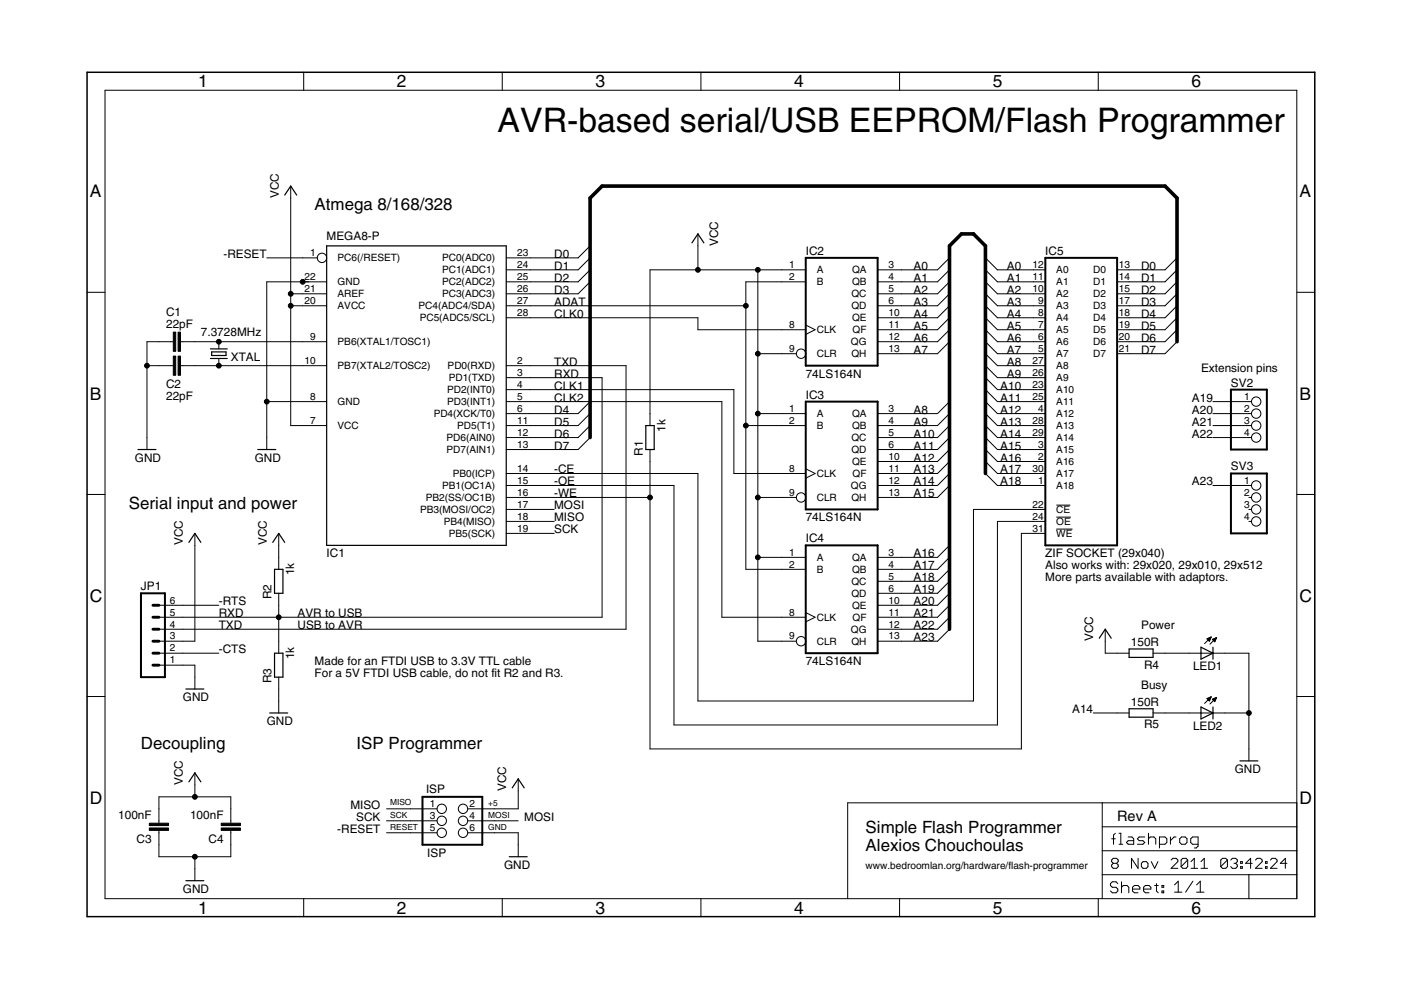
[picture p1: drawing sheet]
<svg xmlns="http://www.w3.org/2000/svg" width="297mm" height="210mm" viewBox="0 0 297 210" stroke-linecap="round" stroke-linejoin="round" font-family="sans-serif">
<defs><g id="words">
<text font-size="7.2" x="105.5" y="28">AVR-based serial/USB EEPROM/Flash Programmer</text>
<g font-size="3.7">
<text x="42" y="18.5">1</text>
<text x="84.1" y="18.5">2</text>
<text x="126.2" y="18.5">3</text>
<text x="168.4" y="18.5">4</text>
<text x="210.5" y="18.5">5</text>
<text x="252.6" y="18.5">6</text>
<text x="19.1" y="41.9">A</text>
<text x="275.6" y="41.9">A</text>
<text x="19.1" y="84.7">B</text>
<text x="275.6" y="84.7">B</text>
<text x="19.1" y="127.6">C</text>
<text x="275.6" y="127.6">C</text>
<text x="19.1" y="170.4">D</text>
<text x="275.6" y="170.4">D</text>
<text x="42" y="193.7">1</text>
<text x="84.1" y="193.7">2</text>
<text x="126.2" y="193.7">3</text>
<text x="168.4" y="193.7">4</text>
<text x="210.5" y="193.7">5</text>
<text x="252.6" y="193.7">6</text>
</g>
<g font-size="3.6">
<text x="66.7" y="44.5">Atmega 8/168/328</text>
<text x="27.3" y="108">Serial input and power</text>
<text x="29.9" y="158.8">Decoupling</text>
<text x="75.6" y="158.8">ISP Programmer</text>
<text x="183.5" y="176.6">Simple Flash Programmer</text>
<text x="183.5" y="180.4">Alexios Chouchoulas</text>
</g>
<text font-size="3.1" x="236.9" y="174">Rev A</text>
<g font-size="2.5">
<text x="59.1" y="42" transform="rotate(-90 59.1 42)">VCC</text>
<text x="69.2" y="50.9">MEGA8-P</text>
<text x="152.3" y="52.1" transform="rotate(-90 152.3 52.1)">VCC</text>
<text x="47.4" y="54.7">-RESET</text>
<text x="117.5" y="54.7">D0</text>
<text x="117.5" y="57.2">D1</text>
<text x="117.5" y="59.8">D2</text>
<text x="170.8" y="54">IC2</text>
<text x="193.7" y="57.2">A0</text>
<text x="193.7" y="59.8">A1</text>
<text x="213.5" y="57.2">A0</text>
<text x="213.5" y="59.8">A1</text>
<text x="221.6" y="54">IC5</text>
<text x="241.9" y="57.2">D0</text>
<text x="241.9" y="59.8">D1</text>
<text x="117.5" y="62.3">D3</text>
<text x="117.5" y="64.8">ADAT</text>
<text x="193.7" y="62.3">A2</text>
<text x="193.7" y="64.8">A3</text>
<text x="213.5" y="62.3">A2</text>
<text x="213.5" y="64.8">A3</text>
<text x="241.9" y="62.3">D2</text>
<text x="241.9" y="64.8">D3</text>
<text x="35.2" y="69.5">22pF</text>
<text x="35.2" y="67">C1</text>
<text x="42.6" y="71.2">7.3728MHz</text>
<text x="117.5" y="67.4">CLK0</text>
<text x="193.7" y="67.4">A4</text>
<text x="193.7" y="69.9">A5</text>
<text x="213.5" y="67.4">A4</text>
<text x="213.5" y="69.9">A5</text>
<text x="241.9" y="67.4">D4</text>
<text x="241.9" y="69.9">D5</text>
<text x="48.9" y="76.5">XTAL</text>
<text x="117.5" y="77.5">TXD</text>
<text x="193.7" y="72.5">A6</text>
<text x="193.7" y="75">A7</text>
<text x="213.5" y="72.5">A6</text>
<text x="213.5" y="75">A7</text>
<text x="213.5" y="77.5">A8</text>
<text x="241.9" y="72.5">D6</text>
<text x="241.9" y="75">D7</text>
<text x="35.2" y="82.2">C2</text>
<text x="117.5" y="80.1">RXD</text>
<text x="117.5" y="82.6">CLK1</text>
<text x="170.8" y="80.1">74LS164N</text>
<text x="212.1" y="82.6">A10</text>
<text x="213.5" y="80.1">A9</text>
<text x="254.6" y="78.8">Extension pins</text>
<text x="261" y="82">SV2</text>
<text x="35.2" y="84.8">22pF</text>
<text x="117.5" y="87.7">D4</text>
<text x="117.5" y="85.2">CLK2</text>
<text x="170.8" y="84.5">IC3</text>
<text x="193.7" y="87.7">A8</text>
<text x="212.1" y="85.2">A11</text>
<text x="212.1" y="87.7">A12</text>
<text x="252.7" y="85.2">A19</text>
<text x="252.7" y="87.7">A20</text>
<text x="117.5" y="90.2">D5</text>
<text x="117.5" y="92.8">D6</text>
<text x="117.5" y="95.3">D7</text>
<text x="141.1" y="91.5" transform="rotate(-90 141.1 91.5)">1k</text>
<text x="193.7" y="90.2">A9</text>
<text x="193.7" y="92.8">A10</text>
<text x="193.7" y="95.3">A11</text>
<text x="212.1" y="90.2">A13</text>
<text x="212.1" y="92.8">A14</text>
<text x="212.1" y="95.3">A15</text>
<text x="252.7" y="90.2">A21</text>
<text x="252.7" y="92.8">A22</text>
<text x="28.6" y="97.9">GND</text>
<text x="54" y="97.9">GND</text>
<text x="117.5" y="100.4">-CE</text>
<text x="136.3" y="96.6" transform="rotate(-90 136.3 96.6)">R1</text>
<text x="193.7" y="97.9">A12</text>
<text x="193.7" y="100.4">A13</text>
<text x="212.1" y="97.9">A16</text>
<text x="212.1" y="100.4">A17</text>
<text x="261" y="99.8">SV3</text>
<text x="117.5" y="105.5">-WE</text>
<text x="117.5" y="102.9">-OE</text>
<text x="193.7" y="102.9">A14</text>
<text x="193.7" y="105.5">A15</text>
<text x="212.1" y="102.9">A18</text>
<text x="252.7" y="102.9">A23</text>
<text x="117.5" y="110.5">MISO</text>
<text x="117.5" y="113.1">SCK</text>
<text x="117.5" y="108">MOSI</text>
<text x="170.8" y="110.5">74LS164N</text>
<text x="38.8" y="115.6" transform="rotate(-90 38.8 115.6)">VCC</text>
<text x="56.6" y="115.6" transform="rotate(-90 56.6 115.6)">VCC</text>
<text x="69.2" y="118.2">IC1</text>
<text x="170.8" y="115">IC4</text>
<text x="193.7" y="118.2">A16</text>
<text x="221.6" y="118.2">ZIF SOCKET (29x040)</text>
<text x="29.9" y="125">JP1</text>
<text x="62.4" y="122" transform="rotate(-90 62.4 122)">1k</text>
<text x="193.7" y="120.7">A17</text>
<text x="193.7" y="123.2">A18</text>
<text x="193.7" y="125.8">A19</text>
<text x="221.6" y="120.7">Also works with: 29x020, 29x010, 29x512</text>
<text x="221.6" y="123.2">More parts available with adaptors.</text>
<text x="46.4" y="130.9">RXD</text>
<text x="46.4" y="128.3">-RTS</text>
<text x="57.6" y="127.1" transform="rotate(-90 57.6 127.1)">R2</text>
<text x="63.1" y="130.9">AVR to USB</text>
<text x="193.7" y="128.3">A20</text>
<text x="193.7" y="130.9">A21</text>
<text x="46.4" y="133.4">TXD</text>
<text x="63.1" y="133.4">USB to AVR</text>
<text x="193.7" y="135.9">A23</text>
<text x="193.7" y="133.4">A22</text>
<text x="231.8" y="135.9" transform="rotate(-90 231.8 135.9)">VCC</text>
<text x="239.8" y="137">150R</text>
<text x="241.9" y="133.4">Power</text>
<text x="46.4" y="138.5">-CTS</text>
<text x="62.4" y="139.8" transform="rotate(-90 62.4 139.8)">1k</text>
<text x="66.7" y="141">Made for an FTDI USB to 3.3V TTL cable</text>
<text x="66.7" y="143.6">For a 5V FTDI USB cable, do not fit R2 and R3.</text>
<text x="170.8" y="141">74LS164N</text>
<text x="242.6" y="141.8">R4</text>
<text x="252.9" y="142">LED1</text>
<text x="38.8" y="148.6">GND</text>
<text x="57.6" y="144.8" transform="rotate(-90 57.6 144.8)">R3</text>
<text x="239.8" y="149.7">150R</text>
<text x="241.9" y="146.1">Busy</text>
<text x="56.6" y="153.7">GND</text>
<text x="227.3" y="151.2">A14</text>
<text x="242.6" y="154.5">R5</text>
<text x="252.9" y="154.7">LED2</text>
<text x="38.8" y="166.4" transform="rotate(-90 38.8 166.4)">VCC</text>
<text x="107.3" y="167.7" transform="rotate(-90 107.3 167.7)">VCC</text>
<text x="261.8" y="163.9">GND</text>
<text x="25.1" y="173.7">100nF</text>
<text x="40.3" y="173.7">100nF</text>
<text x="74.3" y="171.5">MISO</text>
<text x="90.3" y="168.2">ISP</text>
<text x="29" y="178.7">C3</text>
<text x="44.2" y="178.7">C4</text>
<text x="71.5" y="176.6">-RESET</text>
<text x="75.5" y="174">SCK</text>
<text x="111.2" y="174">MOSI</text>
<text x="90.6" y="181.7">ISP</text>
<text x="106.9" y="184.2">GND</text>
<text x="38.8" y="189.3">GND</text>
</g>
<g font-size="2.1">
<text x="64.5" y="59.4">22</text>
<text x="65.7" y="54.3">1</text>
<text x="71.6" y="55.4">PC6(/RESET)</text>
<text x="93.7" y="58">PC1(ADC1)</text>
<text x="93.7" y="55.4">PC0(ADC0)</text>
<text x="109.7" y="59.4">25</text>
<text x="109.7" y="56.9">24</text>
<text x="109.7" y="54.3">23</text>
<text x="167.3" y="56.9">1</text>
<text x="167.3" y="59.4">2</text>
<text x="173.2" y="58">A</text>
<text x="180.6" y="58">QA</text>
<text x="188.4" y="56.9">3</text>
<text x="188.4" y="59.4">4</text>
<text x="218.9" y="59.4">11</text>
<text x="218.9" y="56.9">12</text>
<text x="224" y="58">A0</text>
<text x="231.8" y="58">D0</text>
<text x="237.2" y="56.9">13</text>
<text x="237.2" y="59.4">14</text>
<text x="64.5" y="61.9">21</text>
<text x="64.5" y="64.5">20</text>
<text x="71.6" y="60.5">GND</text>
<text x="71.6" y="63.1">AREF</text>
<text x="71.6" y="65.6">AVCC</text>
<text x="88.8" y="65.6">PC4(ADC4/SDA)</text>
<text x="93.7" y="63.1">PC3(ADC3)</text>
<text x="93.7" y="60.5">PC2(ADC2)</text>
<text x="109.7" y="64.5">27</text>
<text x="109.7" y="61.9">26</text>
<text x="173.2" y="60.5">B</text>
<text x="180.5" y="63.1">QC</text>
<text x="180.5" y="65.6">QD</text>
<text x="180.6" y="60.5">QB</text>
<text x="188.4" y="61.9">5</text>
<text x="188.4" y="64.5">6</text>
<text x="218.9" y="61.9">10</text>
<text x="220.1" y="64.5">9</text>
<text x="224" y="65.6">A3</text>
<text x="224" y="63.1">A2</text>
<text x="224" y="60.5">A1</text>
<text x="231.8" y="60.5">D1</text>
<text x="231.8" y="63.1">D2</text>
<text x="231.8" y="65.6">D3</text>
<text x="237.2" y="61.9">15</text>
<text x="237.2" y="64.5">17</text>
<text x="89" y="68.1">PC5(ADC5/SCL)</text>
<text x="109.7" y="67">28</text>
<text x="167.3" y="69.6">8</text>
<text x="173.2" y="70.7">CLK</text>
<text x="180.6" y="68.1">QE</text>
<text x="180.7" y="70.7">QF</text>
<text x="188.4" y="67">10</text>
<text x="188.4" y="69.6">11</text>
<text x="220.1" y="69.6">7</text>
<text x="220.1" y="67">8</text>
<text x="224" y="70.7">A5</text>
<text x="224" y="68.1">A4</text>
<text x="231.8" y="68.1">D4</text>
<text x="231.8" y="70.7">D5</text>
<text x="237.2" y="67">18</text>
<text x="237.2" y="69.6">19</text>
<text x="64.5" y="77.2">10</text>
<text x="65.7" y="72.1">9</text>
<text x="71.6" y="73.2">PB6(XTAL1/TOSC1)</text>
<text x="109.7" y="77.2">2</text>
<text x="167.3" y="74.6">9</text>
<text x="173.2" y="75.8">CLR</text>
<text x="180.4" y="73.2">QG</text>
<text x="180.5" y="75.8">QH</text>
<text x="188.4" y="72.1">12</text>
<text x="188.4" y="74.6">13</text>
<text x="218.9" y="77.2">27</text>
<text x="220.1" y="74.6">5</text>
<text x="220.1" y="72.1">6</text>
<text x="224" y="75.8">A7</text>
<text x="224" y="73.2">A6</text>
<text x="231.8" y="73.2">D6</text>
<text x="231.8" y="75.8">D7</text>
<text x="237.2" y="72.1">20</text>
<text x="237.2" y="74.6">21</text>
<text x="71.6" y="78.3">PB7(XTAL2/TOSC2)</text>
<text x="94.8" y="83.4">PD2(INT0)</text>
<text x="94.9" y="78.3">PD0(RXD)</text>
<text x="95.1" y="80.8">PD1(TXD)</text>
<text x="109.7" y="82.3">4</text>
<text x="109.7" y="79.7">3</text>
<text x="218.9" y="82.3">23</text>
<text x="218.9" y="79.7">26</text>
<text x="224" y="83.4">A10</text>
<text x="224" y="80.8">A9</text>
<text x="224" y="78.3">A8</text>
<text x="65.7" y="84.8">8</text>
<text x="65.7" y="89.9">7</text>
<text x="71.6" y="85.9">GND</text>
<text x="91.9" y="88.5">PD4(XCK/T0)</text>
<text x="94.8" y="85.9">PD3(INT1)</text>
<text x="109.7" y="89.9">11</text>
<text x="109.7" y="87.3">6</text>
<text x="109.7" y="84.8">5</text>
<text x="167.3" y="87.3">1</text>
<text x="167.3" y="89.9">2</text>
<text x="173.2" y="88.5">A</text>
<text x="180.6" y="88.5">QA</text>
<text x="188.4" y="87.3">3</text>
<text x="188.4" y="89.9">4</text>
<text x="218.9" y="84.8">25</text>
<text x="218.9" y="89.9">28</text>
<text x="220.1" y="87.3">4</text>
<text x="224" y="88.5">A12</text>
<text x="224" y="85.9">A11</text>
<text x="263.8" y="84.8">1</text>
<text x="263.8" y="87.3">2</text>
<text x="263.8" y="89.9">3</text>
<text x="71.6" y="91">VCC</text>
<text x="94.7" y="93.5">PD6(AIN0)</text>
<text x="96.9" y="91">PD5(T1)</text>
<text x="109.7" y="95">13</text>
<text x="109.7" y="92.4">12</text>
<text x="173.2" y="91">B</text>
<text x="180.5" y="93.5">QC</text>
<text x="180.6" y="91">QB</text>
<text x="188.4" y="92.4">5</text>
<text x="188.4" y="95">6</text>
<text x="218.9" y="92.4">29</text>
<text x="220.1" y="95">3</text>
<text x="224" y="91">A13</text>
<text x="224" y="93.5">A14</text>
<text x="263.8" y="92.4">4</text>
<text x="94.7" y="96.1">PD7(AIN1)</text>
<text x="96" y="101.2">PB0(ICP)</text>
<text x="109.7" y="100">14</text>
<text x="167.3" y="100">8</text>
<text x="173.2" y="101.2">CLK</text>
<text x="180.5" y="96.1">QD</text>
<text x="180.6" y="98.6">QE</text>
<text x="180.7" y="101.2">QF</text>
<text x="188.4" y="97.5">10</text>
<text x="188.4" y="100">11</text>
<text x="218.9" y="100">30</text>
<text x="220.1" y="97.5">2</text>
<text x="224" y="96.1">A15</text>
<text x="224" y="98.6">A16</text>
<text x="224" y="101.2">A17</text>
<text x="90.3" y="106.2">PB2(SS/OC1B)</text>
<text x="93.7" y="103.7">PB1(OC1A)</text>
<text x="109.7" y="107.7">17</text>
<text x="109.7" y="105.1">16</text>
<text x="109.7" y="102.6">15</text>
<text x="167.3" y="105.1">9</text>
<text x="173.2" y="106.2">CLR</text>
<text x="180.4" y="103.7">QG</text>
<text x="180.5" y="106.2">QH</text>
<text x="188.4" y="102.6">12</text>
<text x="188.4" y="105.1">13</text>
<text x="218.9" y="107.7">22</text>
<text x="220.1" y="102.6">1</text>
<text x="224" y="103.7">A18</text>
<text x="263.8" y="102.6">1</text>
<text x="263.8" y="105.1">2</text>
<text x="263.8" y="107.7">3</text>
<text x="89.1" y="108.8">PB3(MOSI/OC2)</text>
<text x="94.1" y="111.3">PB4(MISO)</text>
<text x="95.2" y="113.8">PB5(SCK)</text>
<text x="109.7" y="112.7">19</text>
<text x="109.7" y="110.2">18</text>
<text x="218.9" y="112.7">31</text>
<text x="218.9" y="110.2">24</text>
<text x="224" y="113.8">WE</text>
<text x="224" y="108.8">CE</text>
<text x="224" y="111.3">OE</text>
<text x="263.8" y="110.2">4</text>
<text x="167.3" y="117.8">1</text>
<text x="173.2" y="118.9">A</text>
<text x="180.6" y="118.9">QA</text>
<text x="188.4" y="117.8">3</text>
<text x="167.3" y="120.4">2</text>
<text x="173.2" y="121.5">B</text>
<text x="180.5" y="124">QC</text>
<text x="180.6" y="121.5">QB</text>
<text x="188.4" y="120.4">4</text>
<text x="188.4" y="122.9">5</text>
<text x="188.4" y="125.4">6</text>
<text x="36" y="130.5">5</text>
<text x="36" y="128">6</text>
<text x="167.3" y="130.5">8</text>
<text x="173.2" y="131.6">CLK</text>
<text x="180.5" y="126.5">QD</text>
<text x="180.6" y="129.1">QE</text>
<text x="180.7" y="131.6">QF</text>
<text x="188.4" y="128">10</text>
<text x="188.4" y="130.5">11</text>
<text x="36" y="135.6">3</text>
<text x="36" y="133">4</text>
<text x="167.3" y="135.6">9</text>
<text x="173.2" y="136.7">CLR</text>
<text x="180.4" y="134.2">QG</text>
<text x="180.5" y="136.7">QH</text>
<text x="188.4" y="133">12</text>
<text x="188.4" y="135.6">13</text>
<text x="36" y="140.7">1</text>
<text x="36" y="138.1">2</text>
<text x="91.1" y="171.1">1</text>
<text x="91.1" y="173.7">3</text>
<text x="99.5" y="171.1">2</text>
<text x="99.5" y="173.7">4</text>
<text x="91.1" y="176.2">5</text>
<text x="99.5" y="176.2">6</text>
<text x="183.5" y="184.2">www.bedroomlan.org/hardware/flash-programmer</text>
</g>
<g font-size="1.8">
<text x="82.7" y="173.5">SCK</text>
<text x="82.7" y="170.7">MISO</text>
<text x="103.5" y="173.4">MOSI</text>
<text x="103.5" y="171">+5</text>
<text x="82.7" y="176.1">RESET</text>
<text x="103.5" y="176.1">GND</text>
</g>
</g></defs>
<g fill="#000" stroke="#000" stroke-width=".21">
<path d="M22.3 19.1v171.4zM64.4 15.3v3.8zM106.5 15.3v3.8zM148.6 15.3v3.8zM190.7 15.3v3.8zM232.9 15.3v3.8zM22.3 19.1h252.7zM56.6 59.8v25.4zM61.6 39.5v2.5zM64.2 59.8h5.1zM64.2 54.7h3.1zM56.6 59.8h7.6z"/>
<path d="M56.6 54.7h7.6zM64.2 59.8h1.2zM107.3 59.8h5.1zM107.3 57.2h5.1zM107.3 54.7h5.1zM112.4 54.7h10.2zM112.4 57.2h10.2zM112.4 59.8h10.2zM125.1 52.1l-2.5 2.6zM125.1 54.7l-2.5 2.5zM125.1 57.2l-2.5 2.6zM125.1 59.8l-2.5 2.5z"/>
<path d="M137.8 57.2h10.2zM148 49.6v2.5zM148 57.2h12.7zM148 52.1v5.1zM158.1 59.8v5zM160.7 57.2v17.8zM165.8 57.2h5zM165.8 59.8h5zM160.7 57.2h5.1zM158.1 59.8h7.7zM186.1 57.2h5.1zM186.1 59.8h5.1z"/>
<path d="M191.2 57.2h7.6zM191.2 59.8h7.6zM201.3 54.7l-2.5 2.5zM201.3 57.2l-2.5 2.6zM201.3 59.8l-2.5 2.5zM208.9 54.7l2.6 2.5zM208.9 57.2l2.6 2.6zM208.9 59.8l2.6 2.5zM211.5 57.2h7.6zM211.5 59.8h7.6zM219.1 59.8h2.5zM219.1 57.2h2.5z"/>
<path d="M236.9 57.2h2.5zM236.9 59.8h2.5zM239.4 57.2h7.6zM239.4 59.8h7.6zM249.6 54.7l-2.6 2.5zM249.6 57.2l-2.6 2.6zM249.6 59.8l-2.6 2.5zM18.5 62h3.8zM31.2 72.5v5zM31.2 77.5v15.3zM33.7 77.5h2.5zM33.7 72.5h2.5z"/>
<path d="M31.2 72.5h2.5zM31.2 77.5h2.5zM36.2 77.5h.5zM36.2 72.5h.5zM38.3 77.5h.5zM38.3 72.5h.5zM38.8 77.5h2.5zM38.8 72.5h2.5zM46.4 76v1.5zM46.4 72.5v1.5zM41.3 72.5h5.1zM41.3 77.5h5.1z"/>
<path d="M61.6 62.3v2.5zM61.6 42v20.3zM64.2 77.5h5.1zM64.2 72.5h5.1zM64.2 62.3h5.1zM64.2 64.8h5.1zM46.4 72.5h17.8zM46.4 77.5h17.8zM61.6 62.3h2.6zM61.6 64.8h2.6zM107.3 77.5h5.1zM107.3 67.4h5.1z"/>
<path d="M107.3 64.8h5.1zM107.3 62.3h5.1zM112.4 77.5h20.3zM112.4 64.8h45.7zM112.4 67.4h35.6zM112.4 62.3h10.2zM132.7 77.5v55.9zM148 67.4v2.5zM148 69.9h17.8zM158.1 64.8v25.4zM160.7 75v12.7zM165.8 69.9h5z"/>
<path d="M165.8 75h3zM160.7 75h5.1zM170.8 68.9l2 1zM170.8 70.9l2-1zM186.1 62.3h5.1zM186.1 64.8h5.1zM186.1 67.4h5.1zM186.1 69.9h5.1zM186.1 72.5h5.1zM186.1 75h5.1zM191.2 62.3h7.6zM191.2 64.8h7.6z"/>
<path d="M191.2 67.4h7.6zM191.2 69.9h7.6zM191.2 72.5h7.6zM191.2 75h7.6zM201.3 62.3l-2.5 2.5zM201.3 64.8l-2.5 2.6zM201.3 67.4l-2.5 2.5zM201.3 69.9l-2.5 2.6zM201.3 72.5l-2.5 2.5zM208.9 62.3l2.6 2.5zM208.9 64.8l2.6 2.6zM208.9 67.4l2.6 2.5z"/>
<path d="M208.9 69.9l2.6 2.6zM208.9 72.5l2.6 2.5zM208.9 75l2.6 2.5zM208.9 77.5l2.6 2.6zM211.5 62.3h7.6zM211.5 64.8h7.6zM211.5 67.4h7.6zM211.5 69.9h7.6zM211.5 72.5h7.6zM211.5 75h7.6zM211.5 77.5h7.6zM219.1 75h2.5z"/>
<path d="M219.1 72.5h2.5zM219.1 69.9h2.5zM219.1 67.4h2.5zM219.1 64.8h2.5zM219.1 62.3h2.5zM219.1 77.5h2.5zM236.9 62.3h2.5zM236.9 64.8h2.5zM236.9 67.4h2.5zM236.9 69.9h2.5zM236.9 72.5h2.5zM236.9 75h2.5z"/>
<path d="M239.4 62.3h7.6zM239.4 64.8h7.6zM239.4 67.4h7.6zM239.4 69.9h7.6zM239.4 72.5h7.6zM239.4 75h7.6zM249.6 62.3l-2.6 2.5zM249.6 64.8l-2.6 2.6zM249.6 67.4l-2.6 2.5zM249.6 69.9l-2.6 2.6zM249.6 72.5l-2.6 2.5zM275 62h3.8z"/>
<path d="M31.2 92.8v2.5zM56.6 92.8v2.5zM56.6 85.2v7.6zM61.6 64.8v25.4zM64.2 85.2h5.1zM64.2 90.2h5.1zM56.6 85.2h7.6zM61.6 90.2h2.6zM107.3 95.3h5.1zM107.3 92.8h5.1zM107.3 90.2h5.1zM107.3 87.7h5.1z"/>
<path d="M107.3 85.2h5.1zM107.3 82.6h5.1zM107.3 80.1h5.1zM112.4 82.6h43.2zM112.4 85.2h40.7zM112.4 87.7h10.2zM112.4 90.2h10.2zM112.4 92.8h10.2zM112.4 95.3h10.2zM125.1 85.2l-2.5 2.5zM122.6 90.2l2.5-2.5zM125.1 90.2l-2.5 2.6z"/>
<path d="M125.1 92.8l-2.5 2.5zM112.4 80.1h15.3zM137.8 87.7v2.5zM137.8 95.3v2.6zM137.8 57.2v30.5zM153.1 85.2v45.7zM155.6 82.6v17.8zM158.1 90.2h7.7zM158.1 90.2v30.5zM160.7 87.7v17.8zM165.8 87.7h5zM165.8 90.2h5z"/>
<path d="M160.7 87.7h5.1zM170.8 99.4l2 1zM186.1 87.7h5.1zM186.1 90.2h5.1zM186.1 92.8h5.1zM186.1 95.3h5.1zM186.1 97.9h5.1zM191.2 87.7h7.6zM191.2 90.2h7.6zM191.2 92.8h7.6zM191.2 95.3h7.6zM191.2 97.9h7.6z"/>
<path d="M201.3 85.2l-2.5 2.5zM201.3 87.7l-2.5 2.5zM201.3 90.2l-2.5 2.6zM201.3 92.8l-2.5 2.5zM201.3 95.3l-2.5 2.6zM201.3 97.9l-2.5 2.5zM208.9 80.1l2.6 2.5zM208.9 82.6l2.6 2.6zM208.9 85.2l2.6 2.5zM208.9 87.7l2.6 2.5zM208.9 90.2l2.6 2.6zM208.9 92.8l2.6 2.5z"/>
<path d="M208.9 95.3l2.6 2.6zM208.9 97.9l2.6 2.5zM211.5 80.1h7.6zM211.5 82.6h7.6zM211.5 85.2h7.6zM211.5 87.7h7.6zM211.5 90.2h7.6zM211.5 92.8h7.6zM211.5 95.3h7.6zM211.5 97.9h7.6zM219.1 87.7h2.5zM219.1 82.6h2.5z"/>
<path d="M219.1 85.2h2.5zM219.1 80.1h2.5zM219.1 90.2h2.5zM219.1 92.8h2.5zM219.1 95.3h2.5zM219.1 97.9h2.5zM264.8 85.2h.6zM264.8 87.7h.6zM264.8 90.2h.6zM264.8 92.8h.6zM257.2 85.2h7.6zM257.2 87.7h7.6z"/>
<path d="M257.2 90.2h7.6zM257.2 92.8h7.6zM18.5 104.8h3.8zM41.3 113.1v2.5zM59.1 118.2v2.5zM59.1 113.1v2.5zM59.1 115.6v2.6zM107.3 113.1h5.1zM107.3 110.6h5.1zM107.3 108h5.1zM107.3 105.5h5.1zM107.3 102.9h5.1z"/>
<path d="M107.3 100.4h5.1zM112.4 110.6h5.1zM112.4 113.1h5.1zM112.4 108h5.1zM112.4 105.5h25.4zM112.4 100.4h35.6zM137.8 105.5v53.3zM137.8 97.9v7.6zM142.9 102.9v50.8zM112.4 102.9h30.5zM155.6 100.4h10.2zM160.7 105.5v12.7z"/>
<path d="M160.7 118.2h5.1zM165.8 100.4h5zM165.8 105.5h3zM165.8 118.2h5zM160.7 105.5h5.1zM170.8 101.4l2-1zM186.1 100.4h5.1zM186.1 102.9h5.1zM186.1 105.5h5.1zM186.1 118.2h5.1zM191.2 100.4h7.6zM191.2 102.9h7.6z"/>
<path d="M191.2 105.5h7.6zM191.2 118.2h7.6zM201.3 100.4l-2.5 2.5zM201.3 102.9l-2.5 2.6zM201.3 115.6l-2.5 2.6zM201.3 118.2l-2.5 2.5zM206.4 108v40.6zM208.9 100.4l2.6 2.5zM211.5 100.4h7.6zM211.5 102.9h7.6zM211.5 110.6h7.6zM216.6 113.1h2.5z"/>
<path d="M219.1 113.1h2.5zM219.1 108h2.5zM219.1 110.6h2.5zM219.1 100.4h2.5zM219.1 102.9h2.5zM206.4 108h12.7zM224 112.2h3.4zM224 107.1h2.9zM224 109.6h3.1zM264.8 102.9h.6zM264.8 105.5h.6zM264.8 108h.6z"/>
<path d="M264.8 110.6h.6zM257.2 102.9h7.6zM275 104.8h3.8zM33.7 138.5h5.1zM33.7 136h5.1zM33.7 133.4h5.1zM33.7 130.9h5.1zM33.7 128.3h5.1zM38.8 130.9h20.3zM38.8 136h2.5zM38.8 138.5h7.6zM38.8 128.3h7.6z"/>
<path d="M41.3 115.6v20.4zM59.1 125.8v2.5zM59.1 136v2.5zM59.1 128.3v2.6zM59.1 130.9v5.1zM59.1 130.9h68.6zM127.7 80.1v50.8zM38.8 133.4h93.9zM153.1 130.9h12.7zM158.1 120.7h7.7zM160.7 118.2v17.8zM165.8 120.7h5z"/>
<path d="M165.8 130.9h5zM165.8 136h3zM160.7 136h5.1zM170.8 129.9l2 1zM170.8 131.8l2-.9zM186.1 120.7h5.1zM186.1 123.3h5.1zM186.1 125.8h5.1zM186.1 128.3h5.1zM186.1 130.9h5.1zM186.1 133.4h5.1zM186.1 136h5.1z"/>
<path d="M191.2 120.7h7.6zM191.2 123.3h7.6zM191.2 125.8h7.6zM191.2 136h7.6zM191.2 128.3h7.6zM191.2 130.9h7.6zM191.2 133.4h7.6zM201.3 120.7l-2.5 2.6zM201.3 123.3l-2.5 2.5zM201.3 133.4l-2.5 2.6zM201.3 125.8l-2.5 2.5zM201.3 128.3l-2.5 2.6z"/>
<path d="M201.3 130.9l-2.5 2.5zM234.3 133.4v2.6zM234.3 136v2.5zM236.9 138.5h2.5zM234.3 138.5h2.6zM244.5 138.5h2.5zM252.1 138.5h2.5zM247 138.5h5.1zM254.6 138.5h2.6zM255.4 136.5l1.4-1.4zM255.9 135.4l.5 .6zM256 135.5h.6z"/>
<path d="M256 135.4h.7zM256.1 135.6h.5zM256.2 135.8h.3zM256.3 135.3h.4zM256.8 135.1l-.4 .9zM256.5 136.6l1.4-1.4zM256.6 135.1h.1zM255.9 135.4l.9-.3zM257 135.6l.6 .5zM257.1 135.6h.6zM257.2 135.5h.6zM257.2 135.8h.5z"/>
<path d="M257.4 135.9h.2zM257.4 135.4h.4zM257.9 135.2l-.3 .9zM257.7 135.3h.2zM257 135.6l.9-.4zM257.2 138.5h2.5zM259.7 138.5h5.1zM264.8 138.5v12.7zM18.5 147.7h3.8zM33.7 141h5.1zM38.8 141h2.5zM41.3 143.6v2.5z"/>
<path d="M41.3 141v2.6zM59.1 143.6v2.5zM59.1 148.6v2.6zM59.1 146.1v2.5zM137.8 158.8h78.8zM142.9 153.7h68.6zM148 100.4v48.2zM148 148.6h58.4zM211.5 110.6v43.1zM216.6 113.1v45.7zM236.9 151.2h2.5zM231.8 151.2h5.1z"/>
<path d="M244.5 151.2h2.5zM252.1 151.2h2.5zM247 151.2h5.1zM254.6 151.2h2.6zM256.8 147.7l-1.4 1.4zM255.9 148.1l.5 .5zM255.9 148.2h.7zM256.1 148.3h.5zM256.1 148.1h.6zM256.2 148.4h.3zM256.3 148.5h.2zM256.4 147.9h.3z"/>
<path d="M256.8 147.7l-.4 .9zM256.5 149.3l1.4-1.4zM255.9 148.1l.9-.4zM257 148.2l.6 .6zM257.1 148.3h.7zM257.2 148.4h.5zM257.3 148.2h.5zM257.3 148.5h.4zM257.4 148.7h.2zM257.5 148.1h.4zM257.9 147.9l-.3 .9zM257 148.2l.9-.3z"/>
<path d="M257.2 151.2h2.5zM259.7 151.2h5.1zM264.8 158.8v2.5zM264.8 151.2v7.6zM275 147.7h3.8zM33.7 176.6v2.5zM33.7 171.5v2.5zM33.7 176.1v.5zM33.7 174v.5zM33.7 179.1v2.5zM33.7 168.9v2.6zM33.7 168.9h7.6z"/>
<path d="M41.3 163.9v2.5zM41.3 166.4v2.5zM41.3 168.9h7.6zM48.9 176.6v2.5zM48.9 171.5v2.5zM48.9 176.1v.5zM48.9 174v.5zM48.9 168.9v2.6zM87 171.5h5.7zM87 174h5.7zM87 176.6h5.7zM82 171.5h5z"/>
<path d="M82 174h5zM82 176.6h5zM99.2 171.5h5.6zM99.2 174h5.6zM99.2 176.6h5.6zM104.8 176.6h5.1zM104.8 174h5.1zM109.9 179.1v2.5zM109.9 165.1v2.6zM109.9 176.6v2.5zM109.9 167.7v3.8zM104.8 171.5h5.1z"/>
<path d="M179.7 170.2h54zM233.7 170.2h41.3zM233.7 175.3h41.3zM233.7 170.2v5.1zM235.7 177.8h.8zM236.1 177.1v1.9zM236.1 177.1l.4-.4zM237.3 176.7h.3zM237.3 179h.7zM237.6 176.7v2.3zM238.8 178.6l.4-.4zM239.2 177.5h.8z"/>
<path d="M238.8 178.6l.4 .4zM239.2 178.2h1.2zM240 177.5l.4 .3zM240.4 177.8v1.2zM239.2 179h1.2zM241.1 179h1.2zM241.1 177.8l.4-.3zM241.1 177.8l.4 .4zM241.5 177.5h1.2zM242.3 179l.4-.4zM241.5 178.2h.8zM242.3 178.2l.4 .4z"/>
<path d="M243.5 176.7v2.3zM243.5 177.8l.4-.3zM243.9 177.5h.8zM244.7 177.5l.3 .3zM245 177.8v1.2zM245.8 177.5v2.3zM245.8 177.5h1.2zM247 177.5l.4 .3zM245.8 179h1.2zM247.4 177.8v.8zM247 179l.4-.4zM248.2 177.5v1.5z"/>
<path d="M248.2 178.2l.7-.7zM248.9 177.5h.4zM250.1 177.8v.8zM250.1 178.6l.4 .4zM250.5 179h.8zM250.5 177.5l-.4 .3zM251.3 179l.4-.4zM250.5 177.5h.8zM251.7 177.8v.8zM251.3 177.5l.4 .3zM252.5 177.8v.8zM252.5 178.6l.3 .4z"/>
<path d="M252.8 177.5l-.3 .3zM252.8 179h1.2zM253.2 179.8h.4zM253.6 179.8l.4-.4zM254 177.5v1.9zM252.8 177.5h1.2zM275 170.2v5.1zM22.3 190.5h252.7zM33.7 181.6h7.6zM41.3 184.2v2.5zM41.3 181.6v2.6zM41.3 181.6h7.6z"/>
<path d="M48.9 179.1v2.5zM64.4 190.5v3.8zM106.5 190.5v3.8zM148.6 190.5v3.8zM179.7 170.2v20.3zM190.7 190.5v3.8zM232.9 190.5v3.8zM233.7 185.5v5zM233.7 180.4v5.1zM233.7 180.4h41.3zM233.7 175.3v5.1zM235.4 187.3v.4z"/>
<path d="M235.4 187.7l.4 .4zM236 182l-.3 .3zM235.7 183.4v.3zM236 183l-.3 .4zM235.7 182.3v.4zM235.4 187.3l.4-.3zM235.8 188.1h.8zM235.4 188.9l.4 .4zM236 182h.7zM235.7 183.7l.3 .4zM235.7 182.7l.3 .3zM236 183h.7z"/>
<path d="M235.8 187h.8zM236.6 188.1l.4 .4zM235.8 189.3h.8zM236.7 182l.4 .3zM236.7 183l.4 .4zM236 184.1h.7zM236.6 187l.4 .3zM237 188.5v.4zM237 188.9l-.4 .4zM237.1 182.3v.4zM237.1 182.7l-.4 .3zM237.1 183.4v.3z"/>
<path d="M237.1 183.7l-.4 .4zM237.8 187v2.3zM237.8 188.1l.4-.4zM238.2 187.7h.7zM238.9 187.7l.4 .4zM239.3 188.1v1.2zM239.9 182v2.1zM239.9 182l1.4 2.1zM240.1 188.1v.8zM240.1 188.1l.4-.4zM240.1 188.9l.4 .4zM240.5 187.7h.8z"/>
<path d="M240.5 189.3h.8zM241.3 187.7l.4 .4zM241.3 182v2.1zM241.7 188.1v.4zM240.1 188.5h1.6zM242 183v.7zM242 183.7l.4 .4zM242.4 184.1h.7zM242.4 182.7l-.4 .3zM242.5 188.1v.8zM242.5 188.1l.3-.4zM242.5 188.9l.3 .4z"/>
<path d="M242.8 187.7h.8zM243.4 183.7l-.3 .4zM242.4 182.7h.7zM243.4 183v.7zM243.1 182.7l.3 .3zM242.8 189.3h.8zM243.6 187.7l.4 .4zM244 188.1v.4zM242.5 188.5h1.5zM244.1 182.7l.7 1.4zM244.8 187.7h.8zM245.5 182.7l-.7 1.4z"/>
<path d="M245.2 187.3v1.6zM245.2 188.9l.4 .4zM246.4 187.7h.3zM246.4 187.7v.4zM246.4 188.9h.3zM246.4 188.9v.4zM246.7 187.7v.4zM246.4 188.1h.3zM246.7 188.9v.4zM246.4 189.3h.3zM248.3 184.1l1.4-1.4zM248.7 182l-.4 .3z"/>
<path d="M249 187.6l.8-.8zM249 189.2h1.6zM248.7 182h.7zM248.3 184.1h1.4zM249.7 182.3v.4zM249.4 182l.3 .3zM249.8 186.8v2.4zM250.4 182.3v1.4zM250.8 182l-.4 .3zM251.8 182.3l-1.4 1.4zM250.8 182h.7zM250.4 183.7l.4 .4z"/>
<path d="M252.9 186.8l-1.5 2.4zM251.5 182l.3 .3zM250.8 184.1h.7zM251.8 182.3v1.4zM251.8 183.7l-.3 .4zM252.5 182.7l.7-.7zM252.5 184.1h1.4zM253.2 182v2.1zM253.7 187.6l.8-.8zM253.7 189.2h1.6zM254.5 186.8v2.4zM254.6 182.7l.7-.7z"/>
<path d="M254.6 184.1h1.4zM255.3 182v2.1zM258.8 182.3v1.4zM258.8 182.3l.4-.3zM258.8 183.7l1.4-1.4zM259.2 182h.7zM258.8 183.7l.4 .4zM259.9 182l.3 .3zM259.2 184.1h.7zM260.2 182.3v1.4zM260.2 183.7l-.3 .4zM261.3 182l-.4 .3z"/>
<path d="M261.3 182h.7zM260.9 183.7l.4 .4zM262 182l.3 .3zM261.6 183h.4zM262 183l.3 .4zM261.3 184.1h.7zM262.3 182.3v.4zM262.3 182.7l-.3 .3zM262.3 183.4v.3zM262.3 183.7l-.3 .4zM263 182.7h.4zM263 182.7v.3z"/>
<path d="M263 183.7h.4zM263 183.7v.4zM263.4 182.7v.3zM263 183h.4zM263.4 183.7v.4zM263 184.1h.4zM264.1 183h1.4zM264.8 185.5v5zM264.8 185.5h10.2zM233.7 185.5h31.1zM265.2 182v2.1zM264.1 183l1.1-1z"/>
<path d="M266.2 184.1l1.4-1.4zM266.5 182l-.3 .3zM266.5 182h.7zM266.2 184.1h1.4zM267.6 182.3v.4zM267.2 182l.4 .3zM268.3 182.7h.3zM268.3 182.7v.3zM268.3 183.7h.3zM268.3 183.7v.4zM268.6 182.7v.3zM268.3 183h.3z"/>
<path d="M268.6 183.7v.4zM268.3 184.1h.3zM270.8 182.7l-1.4 1.4zM269.7 182l-.3 .3zM269.7 182h.7zM269.4 184.1h1.4zM270.8 182.3v.4zM270.4 182l.4 .3zM271.5 183h1.4zM272.5 182v2.1zM272.5 182l-1 1zM275 185.5v5z"/>
<path d="M275 180.4v5.1zM275 175.3v5.1zM275 19.1v171.4z"/>
<circle cx="64.2" cy="59.8" r=".51"/>
<circle cx="148" cy="57.2" r=".51"/>
<circle cx="160.7" cy="57.2" r=".51"/>
<circle cx="31.2" cy="77.5" r=".51"/>
<circle cx="46.4" cy="72.5" r=".51"/>
<circle cx="46.4" cy="77.5" r=".51"/>
<circle cx="61.6" cy="64.8" r=".51"/>
<circle cx="61.6" cy="62.3" r=".51"/>
<circle cx="158.1" cy="64.8" r=".51"/>
<circle cx="160.7" cy="75" r=".51"/>
<circle cx="56.6" cy="85.2" r=".51"/>
<circle cx="158.1" cy="90.2" r=".51"/>
<circle cx="160.7" cy="87.7" r=".51"/>
<circle cx="137.8" cy="105.5" r=".51"/>
<circle cx="160.7" cy="118.2" r=".51"/>
<circle cx="160.7" cy="105.5" r=".51"/>
<circle cx="59.1" cy="130.9" r=".51"/>
<circle cx="264.8" cy="151.2" r=".51"/>
<circle cx="41.3" cy="168.9" r=".51"/>
<circle cx="41.3" cy="181.6" r=".51"/>
</g>
<path d="M18.5 15.3v179zM18.5 15.3h260.3zM18.5 194.3h260.3zM278.8 15.3v179z" fill="#000" stroke="#000" stroke-width=".32"/>
<g fill="#000" stroke="#000" stroke-width=".25">
<path d="M61.6 39.5l-1.2 1.9zM61.6 39.5l1.3 1.9zM69.3 52.1h38zM107.3 52.1v63.5zM148 49.6l-1.3 1.9zM148 49.6l1.2 1.9zM44.9 74.6v.8zM44.9 75.4h3zM44.9 74.6h3zM47.9 74.6v.8zM44.6 76h3.6zM44.6 74h3.6z"/>
<path d="M29.3 95.3h3.8zM54.7 95.3h3.8zM136.9 90.2v5.1zM138.7 90.2v5.1zM136.9 90.2h1.8zM136.9 95.3h1.8zM41.3 113.1l-1.3 1.9zM41.3 113.1l1.3 1.9zM59.1 113.1l-1.3 1.9zM59.1 113.1l1.3 1.9zM69.3 52.1v63.5zM69.3 115.6h38z"/>
<path d="M58.2 120.7v5.1zM58.2 138.5v5.1zM60 120.7v5.1zM58.2 120.7h1.8zM58.2 125.8h1.8zM58.2 138.5h1.8zM234.3 133.4l-1.2 1.9zM234.3 133.4l1.3 1.9zM239.4 139.4h5.1zM239.4 137.6v1.8zM239.4 137.6h5.1zM244.5 137.6v1.8z"/>
<path d="M254.6 139.8l2.6-1.3zM254.6 138.5v1.3zM254.6 137.2v1.3zM254.6 137.2l2.6 1.3zM257.2 138.5v1.3zM257.2 137.2v1.3zM39.4 146.1h3.8zM57.2 151.2h3.8zM60 138.5v5.1zM58.2 143.6h1.8zM239.4 152.1h5.1zM239.4 150.3v1.8z"/>
<path d="M239.4 150.3h5.1zM244.5 150.3v1.8zM254.6 152.4l2.6-1.2zM254.6 151.2v1.2zM254.6 149.9v1.3zM254.6 149.9l2.6 1.3zM257.2 151.2v1.2zM257.2 149.9v1.3zM41.3 163.9l-1.3 1.9zM41.3 163.9l1.3 1.9zM109.9 165.1l-1.3 1.9zM109.9 165.1l1.2 1.9z"/>
<path d="M262.9 161.3h3.8zM39.4 186.7h3.8zM108 181.6h3.8z"/>
</g>
<g fill="none" stroke="#000" stroke-width=".21">
<circle cx="68.3" cy="54.7" r=".99"/>
<circle cx="169.8" cy="75" r=".99"/>
<circle cx="266.3" cy="87.7" r="1"/>
<circle cx="266.3" cy="92.8" r="1"/>
<circle cx="266.3" cy="90.2" r="1"/>
<circle cx="266.3" cy="85.2" r="1"/>
<circle cx="169.8" cy="105.5" r=".99"/>
<circle cx="266.3" cy="108" r="1"/>
<circle cx="266.3" cy="110.6" r="1"/>
<circle cx="266.3" cy="102.9" r="1"/>
<circle cx="266.3" cy="105.5" r="1"/>
<circle cx="169.8" cy="136" r=".99"/>
<circle cx="93.7" cy="176.6" r=".99"/>
<circle cx="93.7" cy="171.5" r=".99"/>
<circle cx="93.7" cy="174" r=".99"/>
<circle cx="98.2" cy="176.6" r=".99"/>
<circle cx="98.2" cy="171.5" r=".99"/>
<circle cx="98.2" cy="174" r=".99"/>
</g>
<path d="M36.7 75.5h.6v4.1h-.6zM36.7 70.4h.6v4.1h-.6zM37.8 75.5h.5v4.1h-.5zM37.8 70.4h.5v4.1h-.5zM31.7 174.5h4v.5h-4zM31.7 175.6h4v.5h-4zM46.9 174.5h4.1v.5h-4.1zM46.9 175.6h4.1v.5h-4.1z" fill="#000" stroke="#000" stroke-width=".21"/>
<g fill="#000" stroke="#000" stroke-width=".42">
<path d="M170.8 54.7v22.8zM170.8 54.7h15.3zM221.6 54.7v60.9zM221.6 54.7h15.3zM170.8 77.5h15.3zM186.1 54.7v22.8zM170.8 85.2v22.8zM170.8 85.2h15.3zM261 95.3h7.6zM261 82.6v12.7zM268.6 82.6v12.7zM261 82.6h7.6z"/>
<path d="M170.8 108h15.3zM170.8 115.6v22.9zM186.1 85.2v22.8zM170.8 115.6h15.3zM221.6 115.6h15.3zM236.9 54.7v60.9zM261 113.1h7.6zM261 100.4v12.7zM268.6 100.4v12.7zM261 100.4h7.6zM29.9 125.8v17.8zM29.9 125.8h5.1z"/>
<path d="M170.8 138.5h15.3zM186.1 115.6v22.9zM29.9 143.6h5.1zM35 125.8v17.8zM89.6 179.1h12.7zM89.6 168.9v10.2zM102.3 168.9v10.2zM89.6 168.9h12.7z"/>
</g>
<path d="M32.4 136h1.3zM32.4 138.5h1.3zM32.4 130.9h1.3zM32.4 133.4h1.3zM32.4 128.3h1.3zM32.4 141h1.3z" fill="#000" stroke="#000" stroke-width=".61"/>
<path d="M127.7 39.5h119.3zM247 39.5l2.6 2.5zM125.1 42l2.6-2.5zM201.3 52.1v81.3zM201.3 52.1l2.6-2.5zM203.9 49.6h2.5zM206.4 49.6l2.5 2.5zM208.9 52.1v48.3zM249.6 42v30.5zM125.1 42v50.8z" fill="#000" stroke="#000" stroke-width=".76"/>
<use href="#words"/>
</svg>
